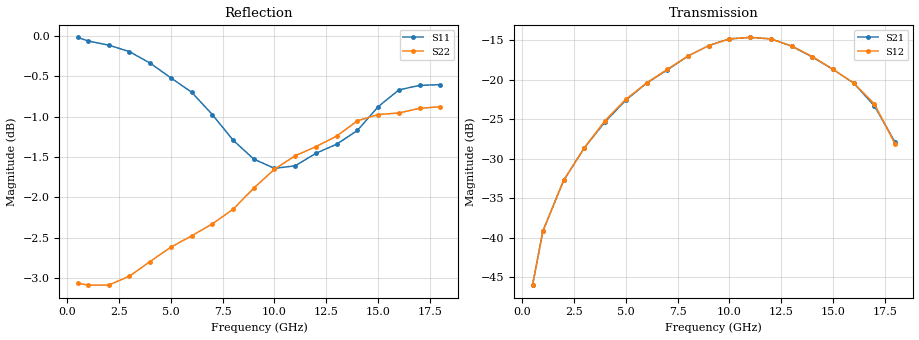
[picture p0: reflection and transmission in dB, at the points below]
!ATF-36163
!VDS=0 VGS=0
! last updated 11-10-95
# ghz s ma r 50
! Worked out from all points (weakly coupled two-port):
!   19 points, 500 MHz to 18 GHz, reference 50 ohm
!   highest |S21| = -14.66 dB at 11 GHz (marker M1); lowest = -46.0 dB at 500 MHz (marker M2)
!   lowest |S11| = -1.6 dB at 10 GHz (marker M3), VSWR 10.63, Z = 5.79 + j23.9 ohm
!   |S11| at or under -10 dB: nowhere
!   |S22| runs from -3.1 to -0.9 dB; largest |S21 - S12| = 0.0027
!   S11 on the Smith chart (normalised r, x): 500 MHz: 0, -11; 5 GHz: 0.05, -0.91; 8 GHz: 0.07, -0.11; 11 GHz: 0.17, +0.92; 14 GHz: 4.53, +6.79; 18 GHz: 0.17, -1.97
0.5  0.998 -10.1  0.005 79.8  0.005 85.9  0.703 169.7
1  0.993 -19.5  0.011 81.0  0.011 82.5  0.701 159.7
2  0.987 -37.3  0.023 74.9  0.023 76.1  0.701 138.9
3  0.978 -55.0  0.037 66.9  0.037 67.5  0.71 118.5
4  0.962 -74.2  0.054 56.2  0.055 56.6  0.725 99.4
5  0.942 -95.2  0.074 41.8  0.075 42.2  0.74 81.0
6  0.923 -117.6  0.095 26.5  0.095 26.9  0.752 63.0
7  0.894 -141.8  0.115 10.6  0.116 11.0  0.765 45.9
8  0.862 -167.7  0.141 -5.6  0.141 -5.5  0.781 30.3
9  0.839 162.5  0.164 -24.1  0.164 -23.8  0.805 15.6
10  0.828 128.4  0.181 -44.1  0.181 -43.9  0.827 2.7
11  0.831 94.0  0.185 -64.1  0.185 -63.8  0.843 -9.7
12  0.846 63.5  0.181 -83.5  0.181 -83.1  0.854 -22.5
13  0.857 35.5  0.163 -101.4  0.163 -101.1  0.867 -34.4
14  0.874 11.7  0.139 -115.7  0.14 -115.3  0.886 -44.2
15  0.904 -8.0  0.116 -128.8  0.116 -128.7  0.894 -53.4
16  0.926 -23.9  0.095 -140.2  0.095 -139.9  0.896 -62.5
17  0.932 -39.1  0.068 -154.0  0.07 -152.4  0.902 -71.1
18  0.933 -53.5  0.04 -161.2  0.039 -161.1  0.904 -80.9
